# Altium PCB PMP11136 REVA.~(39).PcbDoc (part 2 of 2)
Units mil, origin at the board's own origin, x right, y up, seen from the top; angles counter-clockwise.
Board outline 4320 x 3450 mil, 4 copper layers (Top Layer, Signal Layer 1, Signal Layer 2, Bottom Layer), stack 79.834 mil thick; 234 components, 94 nets, 538 pads, 108 vias.
Unrouted connection lines stored in the file: 420.

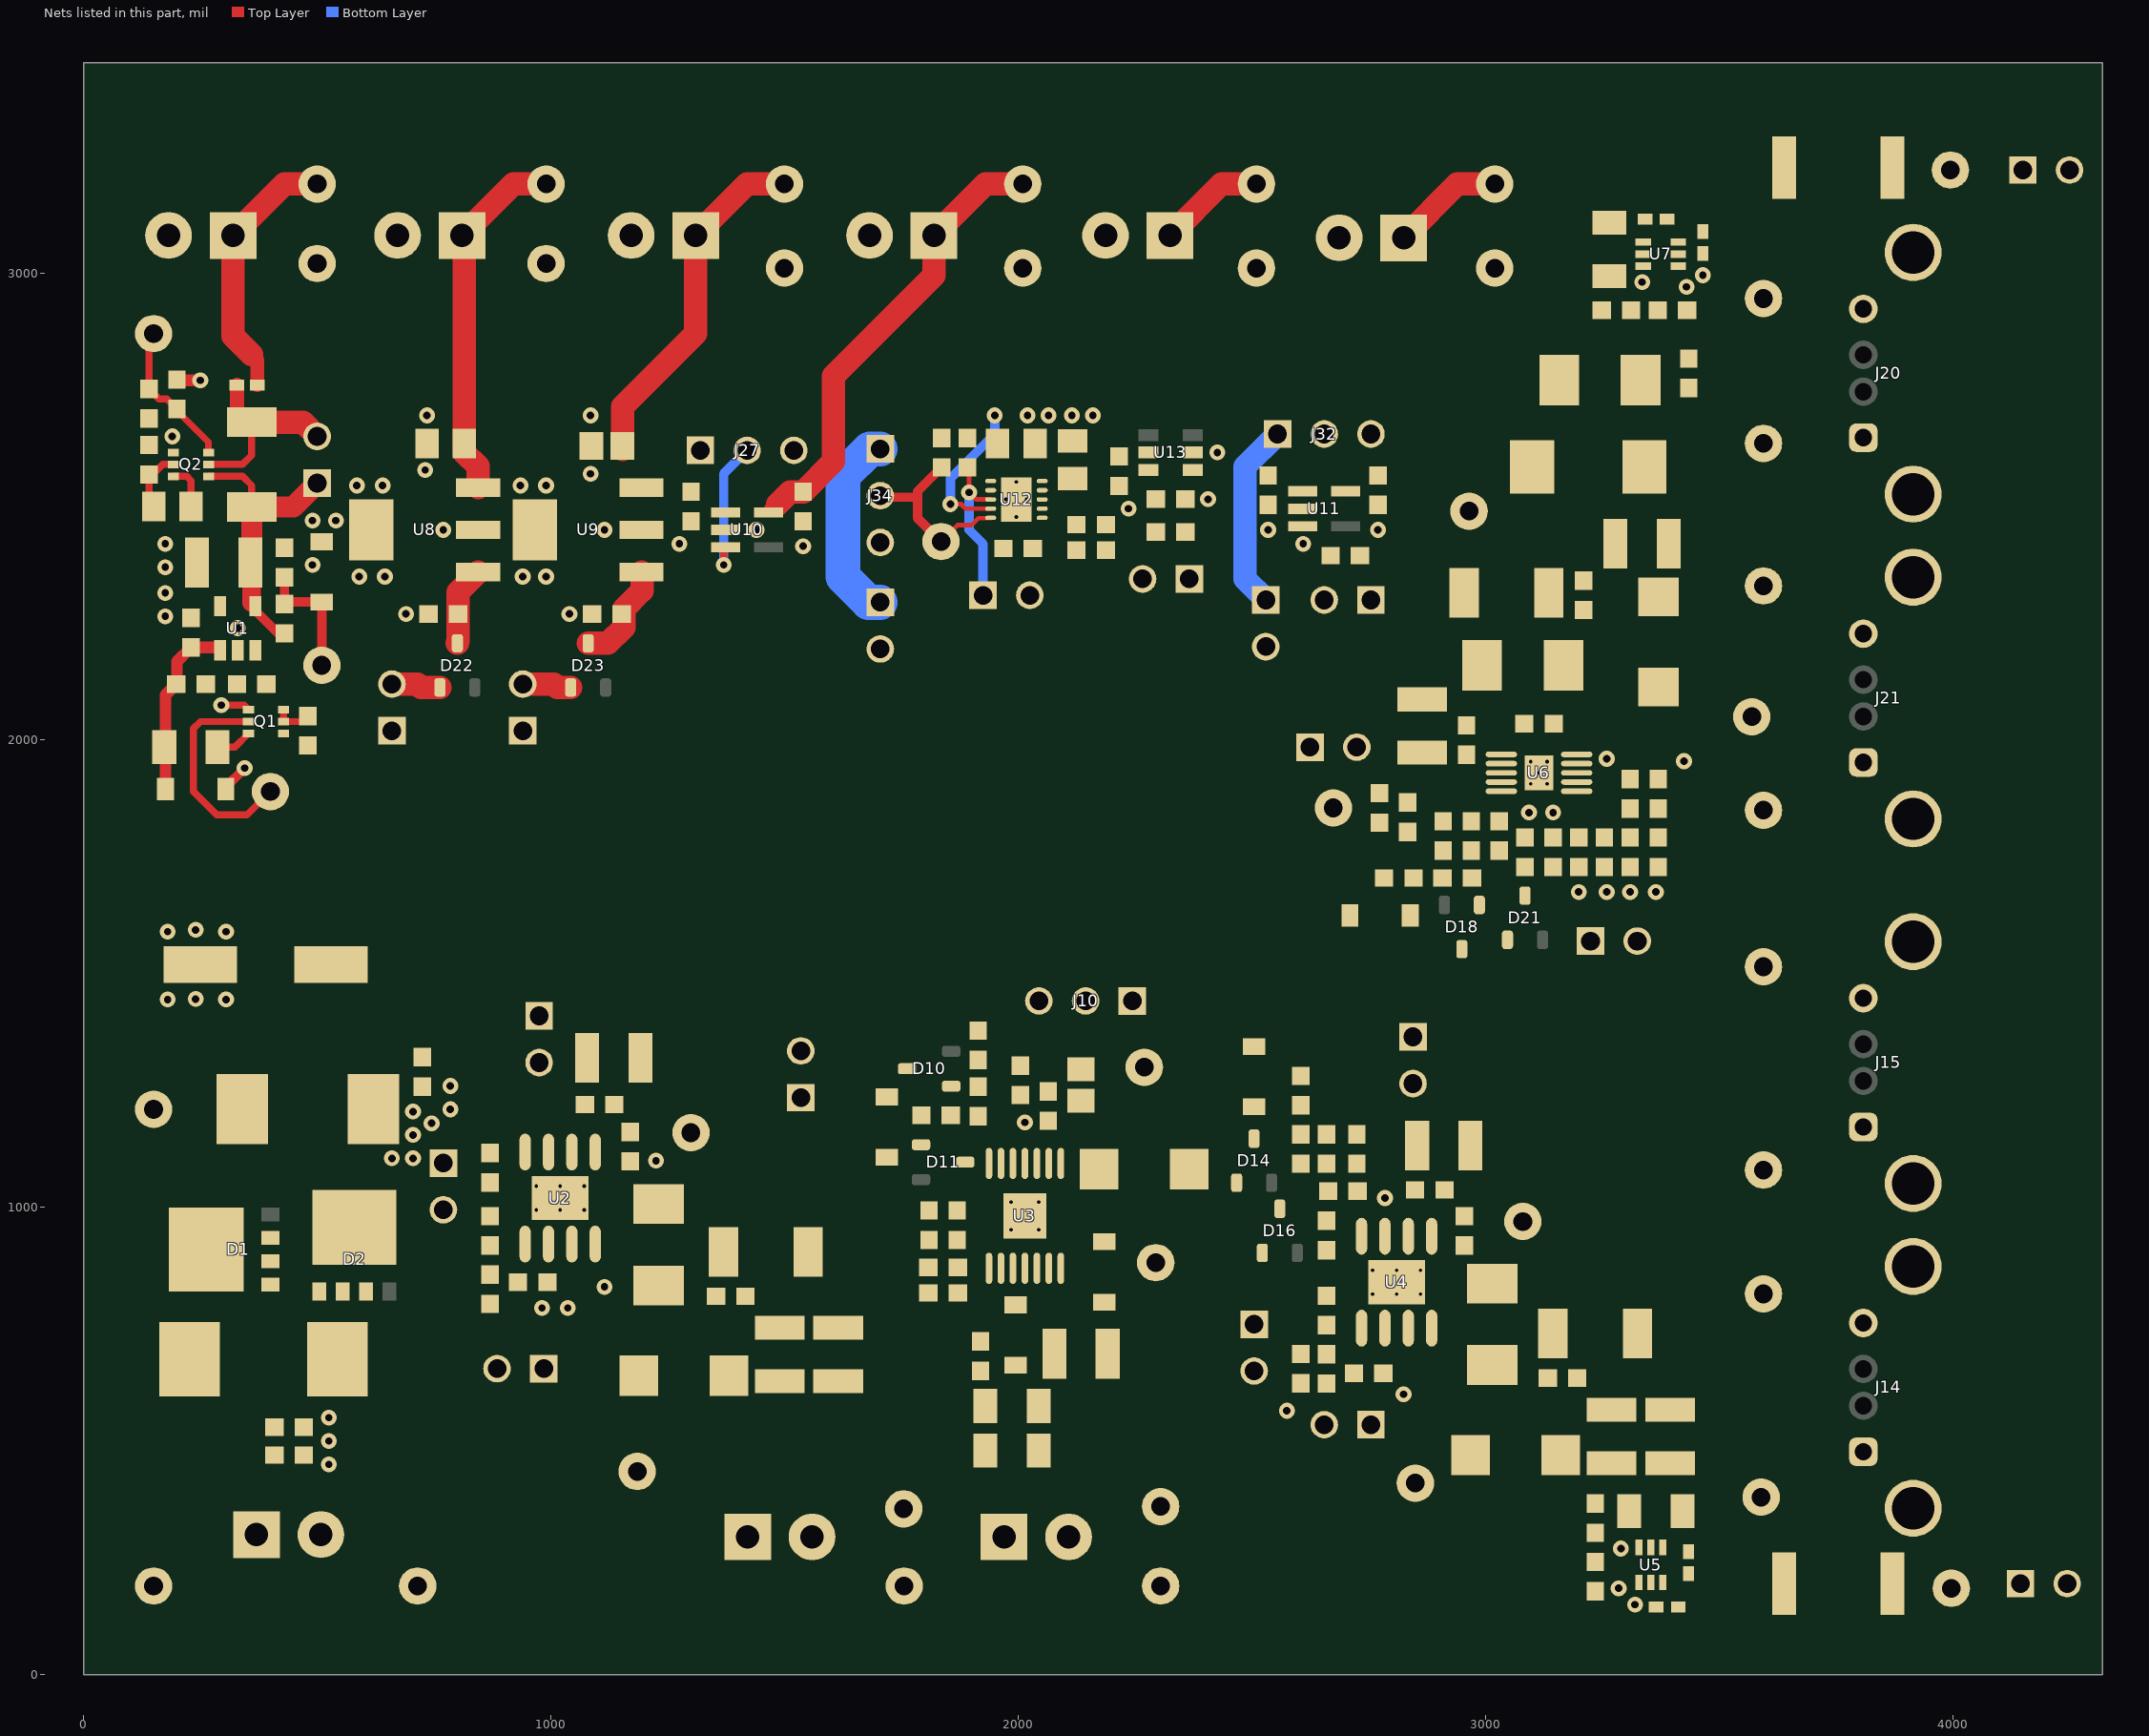
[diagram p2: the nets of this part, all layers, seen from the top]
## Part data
C1 C59: "CAP, CERM, 1000 pF, 100 V, +/- 5%, C0G/NP0, 0603"
C2: "CAP, CERM, 0.01 µF, 100 V, +/- 10%, X7R, 0603"
C3: "CAP, CERM, 0.22 µF, 50 V, +/- 10%, X7R, 0603"
C4: "CAP, AL, 100 µF, 50 V, +/- 20%, 0.34 ohm, SMD"
C5 C9 C22 C32: library part C3225X7R1E106M, "CAP, CERM, 4.7uF, 50V, +/-20%, X7R, 1210"
C6 C13 C51 C52 C54 C55: library part C1608X7R1C105K, "CAP, CERM, 1uF, 25V, +/-10%, X7R, 0603"
C7 C10 C11 C23 C24 C33 C34 C42 C48 C50 C58: "CAP, CERM, 0.1uF, 50V, +/-10%, X7R, 0603"
C8: "CAP, CERM, 0.01 µF, 50 V, +/- 10%, X7R, 0603"
C12 C49: "CAP, CERM, 10uF, 10V, +/-10%, X7R, 0805"
C14 C16 C29 C44: library part C3225X7R1C226M, "CAP, CERM, 22 µF, 16 V, +/- 20%, X7R, 1210"
C15 C20 C27 C39 C40 C57: library part C1608C0G1H102J, "CAP, CERM, open, 0603"
C17 C30: library part C3225X7R1C226M, "CAP, open, 1210"
C18: "CAP, CERM, 0.047 µF, 50 V, +/- 10%, X7R, 0603"
C19 C31 C35: "CAP, CERM, 150 pF, 50 V, +/- 5%, C0G/NP0, 0603"
C21: "CAP, CERM, 6800 pF, 25 V, +/- 5%, C0G/NP0, 0603"
C25 C28 C36 C45: "CAP, CERM, 0.1uF, 50V, +/-10%, X7R, 0402"
C26 C41 C46: "CAP, CERM, 10 pF, 50 V, +/- 5%, C0G/NP0, 0603"
C37: "CAP, CERM, 0.022 µF, 50 V, +/- 10%, X7R, 0603"
C38: "CAP, CERM, 1500 pF, 50 V, +/- 5%, C0G/NP0, 0603"
C43: library part 10TPB220M, "CAP, open, 7343-40 SMD"
C47 C53 C56: "CAP, CERM, 10 µF, 10 V, +/- 10%, X7R, 0805"
D1 D2: "Diode, Schottky, 45 V, 10 A, 6.15x1.00x5.15mm"
D3: library part 1.5SMC6.8A, "Diode, TVS, Uni, 33 V, 1500 W, SMC"
D4: library part 1PS79SB70,115, "Diode, Schottky, 30 V, 0.2 A, SOD-523"
D5: "Diode, Zener, 3.3 V, 500 mW, SOD-123"
D6: "Diode, Zener, 18 V, 500 mW, SOD-123"
D7: library part B130LAW-7-F, "Diode, Schottky, 30V, 1.5A, SOD-123"
D8: "Diode, Zener, 12 V, 500 mW, SOD-123"
D9 D13: library part MBRS260T3G, "Diode, Schottky, 60V, 3A, SMB"
D10 D11 D14 D16 D18 D21 D22 D23: "Diode, Ultrafast, 75V, 0.3A, SOT-23"
D12 D15 D20: "Diode, Zener, 2.4V, 500 mW, SOD-123"
D17 D19: "Diode, Schottky, 60V, 2A, SMB"
J1 J3 J7 J9 J23 J24 J26 J31 J33: "Terminal Block, 6A, 3.5mm Pitch, 2-Pos, TH"
J2 J4 J5 J6 J8 J11 J12 J13 J16 J17 J18 J19 J22 J25 J28 J29 J30 J35 J36: "Header, 100mil, 2x1, Tin, TH"
J10 J27 J32 J34: "Header, 100mil, 3x1, Tin, TH"
J14 J15 J20 J21: "Connector, Receptacle, USB Standard, R/A, Top Mount TH"
L1: "Ferrite Bead, 115 ohm @ 100MHz, 10A, SMD, 2-Leads, Body 8.74x4.65mm"
L2 L4: "Inductor, Wirewound, Ferrite, 2.2 µH, 4.1 A, 0.015 ohm, SMD"
L3 L5: "Inductor, Wirewound, Ferrite, 4.7 µH, 3.1 A, 0.023 ohm, SMD"
Q1: library part "BCR 48PN E6327, Infineon Technologies", "Transistor, NPN/PNP Pair, 50 V, 0.1 A, SOT-363"
Q2: library part "BC 846PN H6327, Infineon Technologies", "Transistor, NPN/PNP Pair, 45 V, 0.1 A, SOT-363"
R1: "RES, 7.5, 5%, 0.75 W, 2010"
R2: "RES, 20.0 k, 1%, 0.1 W, 0603"
R3 R4 R13 R14 R19 R31 R34 R36 R44 R49 R50 R53: "RES, 10.0 k, 1%, 0.1 W, 0603"
R5: "RES, 10.0 k, 1%, 0.125 W, 0805"
R6: "RES, 2.00 k, 1%, 0.25 W, 1206"
R7: "RES, 2.87 k, 1%, 0.1 W, 0603"
R8: "RES, 3.01 k, 1%, 0.1 W, 0603"
R9 R43: "RES, 100 k, 1%, 0.1 W, 0603"
R10: "RES, 34.0 k, 1%, 0.1 W, 0603"
R11: "RES, 110, 1%, 0.1 W, 0603"
R12 R29 R45: library part CRCW20102R70JNEF, "RES, open, 2010"
R15 R26: library part CRCW060312K1FKEA, "RES, 12.1 k, 0.1%, 0.1 W, 0603"
R16: "RES, 53.6 k, 1%, 0.1 W, 0603"
R17 R18: "RES, 15.0, 1%, 0.25 W, 1206"
R20 R28 R38: "RES, 0, 5%, 0.1 W, 0603"
R21 R30 R47: "RES, 200, 1%, 0.1 W, 0603"
R22 R35: "RES, 0.2, 1%, 2 W, 2512"
R23 R37: "RES, 0.01, 1%, 0.5 W, 1206"
R24 R39: "RES, 4.02 k, 1%, 0.1 W, 0603"
R25 R32 R41 R46 R52: "RES, 4.99 k, 1%, 0.1 W, 0603"
R27 R40: "RES, 63.4 k, 1%, 0.1 W, 0603"
R33 R48: "RES, 124 k, 1%, 0.1 W, 0603"
R42: "RES, 54.9 k, 1%, 0.1 W, 0603"
R51: "RES, 2.49 k, 1%, 0.1 W, 0603"
R54: "RES, 49.9 k, 1%, 0.1 W, 0603"
TP1 TP2 TP4 TP6 TP7 TP8 TP9 TP10 TP11 TP12 TP13 TP17 TP19 TP20 TP23 TP25 TP26 TP27 TP30 TP32 TP34 TP36 TP37 TP40 TP41 TP42: "Test Point, Miniature, Red, TH"
TP3 TP5 TP14 TP15 TP16 TP18 TP21 TP22 TP24 TP28 TP29 TP31 TP33 TP35 TP38 TP39: "Test Point, Miniature, Black, TH"
U1: "Low Dropout Voltage Tracking LDO, DBV0005A"
U2 U4: library part LMR14030PDDAR, "LMR14030PQDDAQ1, DDA0008E"
U3: "3-A High Voltage Boost Converter with Soft-start and Programmable Switching Frequency, PWP0014E"
U5 U7: library part INA213AIDCK, "Voltage Output, High or Low Side Measurement, Bi-Directional Zero-Drift Series Current-Shunt Monitor, DCK0006A"
U6: "1.5-A 42-V STEP-DOWN SWIFT DC-DC CONVERTER WITH Eco-mode CONTROL, DGQ0010D"
U8 U9: "High Voltage Ultra Low Iq - Low Drop Out Regulator, DCY0004A"
U10: "Single Output Automotive LDO, 200 mA, Fixed 3.3 V Output, 2 to 5.5 V Input, with Low IQ, 5-pin SOT (DDC), -40 to 125 degC, Green (RoHS & no Sb/Br)"
U11: "Single Output Automotive LDO, 300 mA, Fixed 1.8 V Output, 2 to 5.5 V Input, with Low IQ, 5-pin SOT (DDC), -40 to 125 degC, Green (RoHS & no Sb/Br)"
U12: "Single Output Automotive LDO, 500 mA, Adjustable 0.8 to 3.6 V Output, 0.8 to 5.5 V Input, with Programmable Soft Start, 10-pin SON (DRC), -40 to 125 degC, Green (RoHS & no Sb/Br)"
U13: library part TPS3808G18QDBVRQ1, "LOW-QUIESCENT-CURRENT PROGRAMMABLE-DELAY SUPERVISORY CIRCUIT, DBV0006A"

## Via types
v1: diameter 34, hole 16, Top Layer to Bottom Layer, 83 vias
v2: diameter 19.68, hole 7.87, Top Layer to Bottom Layer, tented top, 12 vias
v3: diameter 19.68, hole 7.87, Top Layer to Bottom Layer, 9 vias
v4: diameter 15.75, hole 7.87, Top Layer to Bottom Layer, 4 vias

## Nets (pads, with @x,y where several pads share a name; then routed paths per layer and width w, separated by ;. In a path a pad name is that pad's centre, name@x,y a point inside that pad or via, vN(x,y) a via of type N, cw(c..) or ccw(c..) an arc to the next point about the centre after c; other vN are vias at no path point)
"3.3V PG": J8.1 J35.2 R13.2 U2.6
  other v1: 981.3,785
3.3V_SW: C16.1 C17.1 C58.1 J6.1 J9.1 J28.2 J29.2 L2.2 R4.2 R10.2 R13.1 R34.1 R36.1 R54.2 TP13.1 U13.6 | length 50.6
  Top Layer w25: R4.2@200,2771.5 201.5,2770 v1(250,2770)
5V#1PG: J16.1 R34.2 U4.6
GND: C1.2 C2.2 C3.2 C4.2 C5.1 C6.2 C7.2 C8.2 C9.1 C10.2 C12.2 C13.2 C14.2 C16.2 C17.2 C18.2 C20.2 C21.2 C22.1 C23.2 C25.2 C28.2 C29.2 C30.2 C32.1 C33.2 C36.2 C37.2 C40.2 C42.2 C43.2 C44.2 C45.2 C46.2 C47.2 C48.2 C49.2 C50.2 C51.2 C52.2 C53.2 C54.2 C55.2 C56.2 C57.2 C58.2 C59.2 D3.2 D5.2 D6.2 D9.2 D11.1 D12.2 D13.2 D15.2 D16.1 D19.2 D20.2 D21.1 J1.2 J3.2 J5.2 J8.2 J9.2 J10.3 J12.2 J13.2 J14.4 J14.5 J14.6 J15.4 J15.5 J15.6 J16.2 J18.2 J19.2 J20.4 J20.5 J20.6 J21.4 J21.5 J21.6 J23.2 J24.2 J26.2 J27.3 J30.2 J31.2 J32.3 J33.2 J34.3 J36.2 Q1.1 Q2.1 R7.2 R8.1 R9.2 R12.1 R14.1 R15.1 R16.1 R17.1 R18.1 R21.1 R29.1 R30.1 R31.1 R32.2 R43.1 R44.1 R45.1 R46.2 R47.1 R52.1 TP3.1 TP5.1 TP15.1 TP16.1 TP18.1 TP21.1 TP22.1 TP24.1 TP28.1 TP29.1 TP31.1 TP33.1 TP35.1 TP38.1 TP39.1 U1.2 U1.5 U2.7 U2.9 U3.7 U3.11 U3.12 U3.13 U3.14 U3.15 U4.7 U4.9 U5.2 U6.9 U6.11 U7.2 U8.2 U8.4 U9.2 U9.4 U10.2 U11.2 U12.6 U12.11 U13.2 | length 123.7
  Top Layer w15: v1(295,2075) 343.31,2075 Q1.1@352.95,2065.36
  Top Layer w20: D6.2@304.47,1895 304.47,1899.47 v1(345,1940)
  other v1: 3320,150 3285,185 525,450 525,500 525,550 2825,600 1036.3,785 660,1105 705,1105 705,1155 745,1180 705,1205 785,1210 785,1260 180,1445 305,1445 239.95,1446 180,1590 305,1590 239.95,1594 3199.68,1675 3364.68,1675 3093.23,1845 3425,1955 3259.68,1960 330,2239.68 175,2265 690,2270 1040,2270 175,2315 590,2350 645,2350 940,2350 990,2350 175,2370 490,2375 1540,2415 175,2420 1275,2420 770,2450 1115,2450 1440,2450 2535,2450 2770,2450 490,2470 540,2470 2236.3,2495.47 2406.3,2515.47 585,2545 640,2545 935,2545 990,2545 1085,2570 730.98,2577.95 2426.3,2615.47 190,2650 735,2695 1085,2695 2020,2695 2065,2695 2115,2695 2160,2695 3430.31,2970 3465.31,2995
  other v2: 2758.82,814.41 2810,814.41 2861.18,814.41 2758.82,865.59 2810,865.59 2861.18,865.59 968.82,994.41 1020,994.41 1071.18,994.41 968.82,1045.59 1020,1045.59 1071.18,1045.59
  other v3: 1996.3,2477.6 1973.66,2515 2018.94,2515 1996.3,2552.4
  other v4: 1984.96,952.38 2044.02,952.38 1984.96,1011.44 2044.02,1011.44
NetC1_1: C1.1 C2.1 J1.1 L1.1 TP1.1
NetC5_2: C5.2 J2.1 Q2.4 R1.1 R3.2 U1.4 | length 615.1
  Top Layer w15: Q2.4@267.4,2564.41 340.59,2564.41 360,2545 R1.1@360,2499.13
  Top Layer w20: U1.4@367.4,2286.93 367.4,2277.6 416.5,2228.5 R3.2@430,2228.5
  Top Layer w25: U1.4@360,2294.33 U1.4@367.4,2286.93
  Top Layer w40: U1.4@360,2294.33 C5.2@360,2377.09
  Top Layer w45: C5.2@360,2377.09 R1.1@360,2499.13 449.13,2499.13 J2.1@500,2550
NetC7_1: C7.1 Q2.6 R4.1 TP6.1 | length 321.3
  Top Layer w15: TP6.1@150,2870 140,2860 C7.1@140,2751.5 161.5,2730 178.5,2730 R4.1@200,2708.5 200,2705 267.4,2637.6 Q2.6@267.4,2615.59
NetC8_1: C8.1 D6.1 R6.2 R9.1 U1.1 | length 391.2
  Top Layer w25: D6.1@175.53,1895 175.53,2097.03 R9.1@198.5,2120 200,2121.5 200,2168.5 C8.1@230,2198.5 286.54,2198.5 U1.1@292.6,2192.44
NetC9_2: C9.2 C10.1 J4.2 U2.2
NetC11_1: C11.1 U2.1
NetC12_1: C12.1 C13.1 J6.2 J10.1 L3.1 TP10.1 U3.3
NetC14_1: C14.1 D7.1 D8.1 J7.2 TP12.1
NetC15_2: C15.2 R12.2
NetC18_1: C18.1 U3.5
NetC19_1: C19.1 D10.1 D11.3 R21.2 U3.6
NetC19_2: C19.2 R20.2
NetC20_1: C20.1 R19.2 U3.8
NetC21_1: C21.1 R19.1
NetC22_2: C22.2 C23.1 J11.2 U4.2
NetC24_1: C24.1 U4.1
NetC24_2: C24.2 C27.1 D13.1 L4.1 TP19.1 U4.8
NetC25_1: C25.1 C29.1 C30.1 J15.1 L4.2 R23.1 R25.1 R27.2 TP20.1 U5.3 U5.5
NetC26_1: C26.1 R24.2
NetC26_2: C26.2 C31.1 D14.1 D16.3 R26.1 R30.2
NetC27_2: C27.2 R29.2
NetC28_1: C28.1 J14.1 R22.1 R23.2 TP41.1 U5.4
NetC31_2: C31.2 R28.2
NetC32_2: C32.2 C33.1 J17.2 U6.2
NetC34_1: C34.1 U6.1
NetC34_2: C34.2 C39.1 D19.1 L5.1 TP26.1 U6.10
NetC35_1: C35.1 C41.2 D18.1 D21.3 R42.1 R47.2
NetC35_2: C35.2 R38.2
NetC36_1: C36.1 C42.1 D17.1 J21.1 R37.1 R40.2 R41.1 TP27.1 U7.3 U7.5
  other v1: 3259.68,1675
NetC37_1: C37.1 U6.4
NetC38_1: C38.1 C46.1 U6.8
NetC38_2: C38.2 R43.2
NetC39_2: C39.2 R45.2
NetC40_1: C40.1 TP25.1 U6.3
NetC41_1: C41.1 R39.2
NetC43_1: C43.1 C44.1 D17.2 L5.2
NetC45_1: C45.1 J20.1 R35.1 R37.2 TP42.1 U7.4
NetC47_1: C47.1 J23.1 TP30.1 U8.3 | length 779.2
  Top Layer w50: U8.3@844.17,2540.55 844.17,2585.83 815,2615 C47.1@815,2635 815,3075 J23.1@810,3080 920,3190 TP30.1@990,3190
NetC48_1: C48.1 D22.3 U8.1 | length 170.5
  Top Layer w50: D22.3@800,2207.24 800.39,2207.64 800.39,2210.39 801.5,2211.5 C48.1@801.5,2270 801.5,2316.77 U8.1@844.17,2359.45
NetC49_1: C49.1 C51.1 J24.1 J27.1 TP32.1 U9.3 U10.1 | length 758.2
  Top Layer w50: C49.1@1153.46,2622.17 C49.1@1153.46,2630 1153.46,2713.46 1310,2870 J24.1@1310,3080 1420,3190 TP32.1@1500,3190
NetC50_1: C50.1 D23.3 U9.1 | length 224.9
  Top Layer w50: D23.3@1080,2207.24 1122.24,2207.24 1156.46,2241.46 1156.46,2281.46 1195,2320 1195,2358.62 U9.1@1194.17,2359.45
NetC52_1: C52.1 J26.1 TP34.1 U10.5 | length 997.3
  Top Layer w20: U10.5@1466,2487.4 1466,2496 1475,2505
  Top Layer w30: 1475,2505 1485,2505
  Top Layer w50: 1485,2505 1511.5,2531.5 C52.1@1540,2531.5 1605,2596.5 1605,2779 1820,2994 J26.1@1820,3080 1930,3190 TP34.1@2010,3190
NetC53_1: C53.1 J28.1 J34.1 R49.2 R50.2 U12.1 U12.2 U12.4 | length 741.4
  Top Layer w10: v1(1855,2505) 1877.75,2505 1887.44,2495.32 U12.4@1941.18,2495.32
  Bottom Layer w20: v1(1855,2505) 1855,2560 1950,2655 v1(1950,2695)
  Bottom Layer w75: J28.1@1705,2295 1680,2295 1625,2350 1625,2565 1683.02,2623.02 J34.1@1705,2623.02
NetC54_1: C54.1 J31.1 TP37.1 U11.5 | length 242.6
  Top Layer w50: J31.1@2825,3075 2940,3190 TP37.1@3020,3190
NetC55_1: C55.1 J29.1 J32.1 U11.1 | length 402.6
  Bottom Layer w50: J29.1@2530,2300 2485,2345 2485,2585 J32.1@2555,2655
NetC56_1: C56.1 C59.1 J33.1 R51.2 TP36.1 U12.9 U12.10 U13.5 | length 230.6
  Top Layer w50: J33.1@2325,3080 2435,3190 TP36.1@2510,3190
NetC57_1: C57.1 U12.7
NetD1_1: D1.1 D1.2 D1.3 D2.1 D2.2 D2.3 L1.2
NetD4_1: D4.1 J3.1 TP4.1 | length 567
  Top Layer w30: 360,2825 371.65,2813.35 D4.1@371.65,2760
  Top Layer w50: 360,2825 320,2865 J3.1@320,3080 430,3190 TP4.1@500,3190
NetD4_2: D4.2 J2.2 Q2.5 R1.2 | length 416.5
  Top Layer w15: Q2.5@267.4,2590 340,2590 360,2610 R1.2@360,2680.24
  Top Layer w20: 328.35,2711.89 R1.2@360,2680.24
  Top Layer w30: 328.35,2711.89 D4.2@328.35,2760
  Top Layer w50: R1.2@360,2680.24 360.24,2680 470,2680 J2.2@500,2650
NetD5_1: D5.1 R3.1 R7.1 TP7.1 | length 274.2
  Top Layer w20: R7.1@430,2348.5 R3.1@430,2291.5 434.04,2295.53 D5.1@510,2295.53 TP7.1@510,2160
NetD7_2: D7.2 L3.2 TP11.1 U3.1 U3.2
NetD8_2: D8.2 R11.2 U3.9
NetD10_3: D10.3 D12.1
NetD14_3: D14.3 D15.1
NetD18_3: D18.3 D20.1
NetD22_1: D22.1 J22.2 | length 105.6
  Top Layer w50: J22.2@660,2120 715,2120 722.24,2112.76 D22.1@762.6,2112.76
NetD23_1: D23.1 J25.2 | length 105.6
  Top Layer w50: J25.2@940,2120 1006.61,2120 1013.86,2112.76 D23.1@1042.6,2112.76
NetJ5_1: J5.1 U2.3
NetJ7_1: J7.1 R11.1 R17.2 R18.2 TP14.1
NetJ10_2: J10.2 U3.4
  other v1: 2014.49,1181.91
NetJ12_1: J12.1 R22.2 TP17.1
NetJ13_1: J13.1 U4.3
  other v1: 2785,1020
NetJ18_1: J18.1 R36.2 U6.6
  other v1: 3144.68,1845
NetJ19_1: J19.1 R35.2 TP23.1
NetJ27_2: J27.2 U10.3 | length 305
  Top Layer w15: v1(1370,2375) 1370,2408.6 U10.3@1374,2412.6
  Bottom Layer w20: v1(1370,2375) 1370,2570 J27.2@1420,2620
NetJ30_1: J30.1 R49.1 U12.3 | length 339.9
  Top Layer w10: R49.1@1891.3,2583.5 1891.3,2568.7 1895,2565 v1(1895,2530) 1910,2515 U12.3@1941.18,2515
  Bottom Layer w20: v1(1895,2530) 1895,2450 1925,2420 J30.1@1925,2310
NetJ32_2: J32.2 R53.2 U11.3
  other v1: 2610,2420
NetJ34_2: J34.2 R50.1 TP40.1 U12.5 | length 408.9
  Top Layer w10: TP40.1@1835,2425 1870,2460 1900,2460 1915,2475 1940.55,2475 U12.5@1941.18,2475.63
  Top Layer w20: J34.2@1705,2523.02 1708.02,2520 1785,2520 ; TP40.1@1835,2425 1785,2475 1785,2520 ; R50.1@1836.3,2583.5 1785,2532.2 1785,2520
NetJ35_1: J35.1 R53.1
NetJ36_1: J36.1 R54.1 U13.1
NetQ1_2: Q1.2 TP8.1 | length 465.2
  Top Layer w15: Q1.2@352.95,2039.77 250.23,2039.77 235,2024.54 235,1890 285,1840 350,1840 TP8.1@400,1890
NetQ1_3: Q1.3 R6.1 | length 77.9
  Top Layer w15: R6.1@287.09,1985 323.77,1985 Q1.3@352.95,2014.18
NetQ1_5: Q1.5 Q1.6 R2.1 | length 82.7
  Top Layer w15: Q1.6@427.75,2065.36 Q1.5@427.75,2039.77 468.27,2039.77 R2.1@480,2051.5
NetQ2_2: Q2.2 R5.1 R8.2 | length 134.1
  Top Layer w15: R5.1@150,2500 140,2510 R8.2@140,2568.5 148.5,2568.5 170,2590 Q2.2@192.6,2590
NetQ2_3: Q2.3 R5.2 | length 96.3
  Top Layer w15: Q2.3@192.6,2564.41 220.59,2564.41 230,2555 R5.2@230,2500
NetR10_1: R10.1 R14.2 U2.5
NetR15_2: R15.2 U2.4
NetR16_2: R16.2 U3.10
NetR24_1: R24.1 R26.2 U4.4
NetR25_2: R25.2 R32.1 U5.1
NetR27_1: R27.1 R31.2 R33.2 U4.5
NetR33_1: R33.1 U5.6
  other v1: 3290,270 2575,565
NetR39_1: R39.1 R42.2 U6.5
NetR40_1: R40.1 R44.2 R48.2 U6.7
  other v3: 3096.97,1906.38 3132.4,1906.38 3114.68,1930 3096.97,1953.62 3132.4,1953.62
NetR41_2: R41.2 R46.1 U7.1
NetR48_1: R48.1 U7.6
  other v1: 3309.68,1675 3335.31,2980
NetR51_1: R51.1 R52.2 U12.8
SYNC: C11.2 C15.1 D9.1 L2.1 R20.1 R28.1 R38.1 TP9.1 U2.8
  other v1: 1115,830 1225,1100
VIN_FLTR: C3.1 C4.1 C6.1 D1.5 D2.5 D3.1 J4.1 J11.1 J17.1 J22.1 J25.1 Q1.4 R2.2 TP2.1 U1.3
pads on no net: D1.4 D2.4 D10.2 D11.2 D14.2 D16.2 D18.2 D21.2 D22.2 D23.2 J14.2 J14.3 J15.2 J15.3 J20.2 J20.3 J21.2 J21.3 U10.4 U11.4 U13.3 U13.4

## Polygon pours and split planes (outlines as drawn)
NetC53_1 on Top Layer "Top Layer-No Net 6" (solid, remove dead copper, pour order 27): 1675,2590 1755,2590 1790,2625 1895,2625 1909.84,2625 1919.84,2615 1922.3,2612.54 1922.3,2605 1922.3,2532.7 1925,2530 1945,2530 1950,2530 1950,2531.09 1957.25,2538.34 1960,2541.09 1960,2575 1980,2595 1980,2606.46 1980,2750 1965,2765 1805,2765 1690,2765 1675,2750
NetC49_1 on Top Layer "Top Layer-No Net 5" (solid, remove dead copper, pour order 25): 1318.7,2515 1155,2515 1130,2540 1130,2650 1345,2650 1350,2645 1350,2620 1350,2590 1375,2565 1385.48,2554.52 1385.48,2477.42 1342.58,2477.42 1305,2515
VIN_FLTR on Top Layer "Top Layer-No Net 4" (solid, remove dead copper, pour order 23): 498.7,2010 431.93,2010 427.75,2014.18 426.93,2015 405,2015 400,2020 400,2110 400,2182.76 375.95,2206.82 355,2185.87 355,2160.94 355,2153.39 370,2138.39 375,2133.39 375,1990 375,1985 390,1970 495,1970
VIN_FLTR on Top Layer "Top Layer-No Net 3" (solid, remove dead copper, pour order 21): 1005,1675 1005,2035 990,2050 620,2050 560,2050 515,2005 461.3,2005 461.3,1861.3 430,1830 350,1750 350,1675
VIN_FLTR on Top Layer "Top Layer-No Net 2" (solid, remove dead copper, pour order 19): 690,875 490,875 490,875.12 470.75,894.37 470,895.12 470,960 470,985 455,1000 355,1000 330,975 330,860 330,855 340,845 340,795 340,785 330,775 130,775 0,775 0,1420 325,1420 345,1440 350,1445 350,1580 350,1595 350,1700 990,1700 1000,1690 1005,1685 1005,1600 1005,1380 845,1380 823.7,1380 743.7,1300 738.7,1305 630,1305 555,1305 545,1295 545,1225 545,1130 560,1115 625,1115 625,1100 650,1075 670,1075 680,1075 690,1065 690,900
NetD1_1 on Top Layer "Top Layer-No Net 1" (solid, remove dead copper, pour order 17): 360,950 360,785 360,775 340,755 330,745 330,740 330,610 340,600 345,595 620,595 620,855 495,855 470,855 450,875 450,930 450,950
NetC1_1 on Top Layer "Top Layer-No Net" (solid, remove dead copper, pour order 15): 0,0 430,0 430,565 415,580 350,580 340,580 315,605 315,755 0,755

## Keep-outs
Keep-Out Layer:
  the board outline again, w7
  text ".Layer_Name" at 577,-858.49 h60

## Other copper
Top Layer:
  text ".Layer_Name" at 577,-858.49 h60
Bottom Layer:
  text ".Layer_Name" at 577,-858.49 h60

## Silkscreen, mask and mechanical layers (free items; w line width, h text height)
Top Overlay:
  text ".PRJ_Number" at 1375,1745 h60
  text ".PCB_Rev" at 1975,1745 h60
  text ".Layer_Name" at 577,-858.49 h60
Bottom Overlay:
  text ".Layer_Name" at 577,-858.49 h60
Top Paste:
  text ".Layer_Name" at 577,-858.49 h60
Bottom Paste:
  text ".Layer_Name" at 577,-858.49 h60
Top Solder:
  text ".Layer_Name" at 577,-858.49 h60
  text ".Layer_Name" at 577,-858.49 h60
Bottom Solder:
  text ".Layer_Name" at 577,-858.49 h60
Drill Guide:
  text ".Layer_Name" at 577,-858.49 h60
M1 Board Outline:
  lines w7: 0,0 4320,0 4320,3450 0,3450 0,0
  lines w10: 0,0 4320,0 4320,3450 0,3450 0,0
  text ".Layer_Name" at 577,-858.49 h60
M2 Board Dimensions:
  rectangle: 125,-400 500,-275
  rectangle: 0,-275 125,-150
  lines w7: 0,-275 1000,-275 ; 125,-400 125,-150 ; 250,-400 250,-150 ; 500,-400 500,-150 ; 750,-400 750,-150 ; 0,-400 0,-150 1000,-150 1000,-400 0,-400
  text ".Layer_Name" at 577,-858.49 h60
M3 3D STEP Top:
  text ".Layer_Name" at 577,-858.49 h60
M4 3D STEP Bottom:
  text ".Layer_Name" at 577,-858.49 h60
M5 Assembly Top:
  lines w10: -292,-930.17 6308,-930.17 ; -292,-726.83 6310,-726.83 ; -292,-523.5 -292,-1133.5 3713,-1133.5 6310,-1133.5 6310,-523.5 -291.5,-523.5 -291.5,-1133.5 1284,-1133.5 ; 2173,-1133.5 2173,-523.5 ; 3440,-726.83 3440,-523.5 ; 4280,-726.83 4280,-523.5 ; 4902,-1140 4902,-937.17
  text "COMPONENTS MARKED 'DNP' SHOULD NOT BE POPULATED." at 1153.5,-318.5 h60
  text "ASSEMBLY VARIANT:" at 1153,-434 h60
  text ".VariantName" at 2189,-434 h60
  text "PCB VIEWED FROM TOP SIDE" at -228.5,-655.67 h60
  text "BOARD #:" at 2248,-655.67 h60
  text ".PRJ_Number" at 2793.5,-655.67 h60
  text "REV:" at 3638,-655.67 h60
  text ".PCB_Rev" at 3929.5,-655.67 h60
  text "SVN REV:" at 4476,-655.67 h60
  text ".VersionControl_RevNumber" at 4982,-655.67 h60
  text "PLOT NAME =" at -228.5,-1064.34 h60
  text ".plot_File_Name" at 577,-1064.34 h60
  text "GENERATED    :" at 2250,-1064.34 h60
  text ".Print_Date" at 3119.5,-1064.34 h60
  text ".Print_Time" at 3848.5,-1064.34 h60
  text "TEXAS INSTRUMENTS" at 5113,-1064.34 h60
M6 Assembly Bottom:
  lines w10: -292.5,-727.33 6309.5,-727.33 ; -290.5,-930.67 6309.5,-930.67 ; 1115.5,-1140.5 1115.5,-937.67 ; 1737.5,-727.33 1737.5,-524 ; 2577.5,-727.33 2577.5,-524 ; 3844.5,-1134 3844.5,-524 ; 4733.5,-1134 6309,-1134 6309,-524 -292.5,-524 -292.5,-1134 2304.5,-1134 6309.5,-1134 6309.5,-524
  text "COMPONENTS MARKED 'DNP' SHOULD NOT BE POPULATED." at 6102,-318 h60
  text ".VariantName" at 5058,-434 h60
  text "ASSEMBLY VARIANT:" at 6097,-434 h60
  text ".VersionControl_RevNumber" at 1035.5,-656.17 h60
  text "SVN REV:" at 1541.5,-656.17 h60
  text ".PCB_Rev" at 2088,-656.17 h60
  text "REV:" at 2379.5,-656.17 h60
  text ".PRJ_Number" at 3224,-656.17 h60
  text "BOARD #:" at 3769.5,-656.17 h60
  text "PCB VIEWED FROM BOTTOM SIDE" at 6246,-656.17 h60
  text "TEXAS INSTRUMENTS" at 904.5,-1064.84 h60
  text ".Print_Time" at 2169,-1064.84 h60
  text ".Print_Date" at 2898,-1064.84 h60
  text "GENERATED    :" at 3767.5,-1064.84 h60
  text ".plot_File_Name" at 5440.5,-1064.84 h60
  text "PLOT NAME =" at 6246,-1064.84 h60
M9 Title Sheet:
  drawing of 57 lines, arcs and shapes, not listed
  text "1" at 739.84,8036.5 h70
  text "2" at 3235.5,8036.5 h70
  text "3" at 5724.84,8036.5 h70
  text "4" at 8231.51,8036.5 h70
  text "5" at 10730.5,8036.5 h70
  text "6" at 13235.5,8036.5 h70
  text "A" at -416.5,6893.5 h70
  text "A" at 14383.5,6893.5 h70
  text "B" at -416.5,4513.5 h70
  text "B" at 14383.5,4513.5 h70
  text "C" at -416.5,2138.5 h70
  text "C" at 14383.5,2138.5 h70
  text "PROJECT TITLE:" at 11343.5,277.5 h45
  text ".PRJ_Title" at 11393.5,144.17 h70
  text "DESIGNED FOR:" at 11343.5,-23.5 h45
  text ".PRJ_Customer" at 11393.5,-163.5 h70
  text "D" at -416.5,-231.5 h70
  text "D" at 14383.5,-231.5 h70
  text "FILE NAME:" at 11343.5,-323.5 h45
  text ".PCB_File_Name_No_Path" at 11393.5,-443.5 h70
  text "Texas Instruments (TI) and/or its licensors do not warrant the accuracy or completeness of this specification" at 6374,-605.34 h45
  text "ENGINEER:" at 11343.5,-613.5 h45
  text "LAYOUT BY:" at 12848.5,-613.5 h45
  text "or any information contained therein. TI and/or its licensors do not warrant that this design will meet" at 6329.01,-718 h45
  text ".PRJ_Engineer" at 11393.5,-768.49 h70
  text ".PCB_Layout" at 12899,-768.49 h70
  text "the specifications, will be suitable for your application or fit for any particular purpose, or will operate in" at 6329.01,-830.67 h45
  text ".Layer_Name" at 577,-858.49 h60
  text "ALTIUM DESIGNER VERSION:" at 12848.5,-923.5 h45
  text "an implementation. TI and/or its licensors do not warrant that the design is production worthy. You should" at 6329.01,-943.33 h45
  text "completely validate and test your design implementation to confirm the system functionality for your application." at 6374,-1056 h45
  text ".print_Scale" at 11393.5,-1056.83 h70
  text ".Application_BuildNumber" at 12899,-1056.83 h70
  text "1" at 739.84,-1263.5 h70
  text "2" at 3235.5,-1263.5 h70
  text "3" at 5724.84,-1263.5 h70
  text "4" at 8231.51,-1263.5 h70
  text "5" at 10730.5,-1263.5 h70
  text "6" at 13235.5,-1263.5 h70
M10 Fab Notes:
  drawing of 185 lines, arcs and shapes, not listed
  text "DESIGN INFORMATION" at 12381.02,5910 h60
  text "MIN. TRACK WIDTH:" at 11736.46,5730 h60
  text "8" at 12832.7,5730 h60
  text "MIL" at 12987.46,5730 h60
  text "MIN. CLEARANCE:" at 11736.46,5598 h60
  text "0.2" at 12772.7,5598 h60
  text "mm" at 12987.46,5598 h60
  text "MIN. VIA PAD SIZE:" at 11736.46,5466 h60
  text "24" at 12802.71,5466 h60
  text "MIL" at 12987.46,5466 h60
  text "0.05mm (2MIL)" at 12431.46,5324.29 h60
  text "MINIMUM ANNULAR RING" at 11407.23,5320 h60
  text "EXTERNAL" at 13139.46,5320 h60
  text "PER" at 11607.23,5202 h60
  text "IPC-D-275 CLASS 2 LEVEL C" at 11827.23,5202 h60
  text "MIL, HOLES" at 13315.46,5089.71 h60
  text "+/-" at 12923,5089 h60
  text "+/-" at 13777,5089 h60
  text "REGISTRATION TOLERANCES:" at 11407.23,5084 h60
  text "METAL" at 12607,5084 h60
  text "5" at 13183.2,5084 h60
  text "3" at 14016.2,5084 h60
  text "MIL" at 14132.46,5084 h60
  text "MATERIAL:" at 11332.46,4874.54 h60
  text "FR-4 High Tg" at 12318.9,4734.21 h60
  text "FR-408" at 11753.46,4725.64 h60
  text "X" at 12165.46,4725.64 h60
  text "OTHER" at 13241.46,4725.64 h60
  text "62 MIL (1.6mm) +/-10%" at 12073.56,4562.92 h60
  text "THICKNESS:" at 11407.23,4558.64 h60
  text "X" at 11945.4,4558.64 h60
  text "OTHER" at 13358.46,4558.64 h60
  text "TOLERANCE:" at 11407.23,4400.64 h60
  text "X" at 12246.53,4400.64 h60
  text "ANSI IPC-6012 TYPE 3 CLASS 2" at 12433.48,4400.64 h60
  text "OTHER +/-" at 12433.46,4244.64 h60
  text "BOW & TWIST:" at 11407.23,4087.64 h60
  text "X" at 12246.53,4087.64 h60
  text "ANSI IPC-6012 TYPE 3 CLASS 2" at 12433.48,4087.64 h60
  text "OTHER +/-" at 12433.46,3929.13 h60
  text "DRILLING:" at 11332.46,3790.64 h60
  text "REFERENCE:" at 11407.23,3673.64 h60
  text "X" at 12055.46,3673.64 h60
  text "AS SHOWN" at 12242.46,3673.64 h60
  text "X" at 12956.46,3673.64 h60
  text "NC_DRILL FILES" at 13093.46,3673.64 h60
  text "PTH MIN COPPER THICKNESS:" at 11407.23,3515.64 h60
  text "X" at 12757.46,3515.64 h60
  text "1MIL" at 12894.46,3515.64 h60
  text "OTHER" at 13391.46,3515.64 h60
  text "BOARD FINISH:" at 11332.46,3356.64 h60
  text "SILKSCREEN:" at 11487.68,3238.64 h60
  text "X" at 12436.46,3238.64 h60
  text "TOP" at 12562.46,3238.64 h60
  text "X" at 12946.46,3238.64 h60
  text "BOTTOM" at 13073.46,3238.64 h60
  text "SILKSCREEN COLOR:" at 11487.68,3071.64 h60
  text "X" at 12435.42,3071.64 h60
  text "WHITE" at 12562.46,3071.64 h60
  text "OTHER" at 13073.46,3071.64 h60
  text "SOLDER RESIST COLOR:" at 11487.68,2901.64 h60
  text "GREEN" at 12182.46,2742.44 h60
  text "BLUE" at 12773.46,2742.44 h60
  text "OTHER" at 13311.46,2742.44 h60
  text "X" at 12650,2740 h60
  text "IMMERSION GOLD (ENIG)" at 12393.46,2553.92 h60
  text "ENEPIG" at 13731,2550.64 h60
  text "SURFACE FINISH:" at 11332.46,2549.64 h60
  text "X" at 11520,2395 h60
  text "IMM. TIN/SILVER OR EQUIV" at 11662,2392.64 h60
  text "OTHER" at 13093.46,2392.64 h60
  text "ARRAY/PANEL:" at 11332.46,2213.64 h60
  text "CUT AND TRIM PER MECH LAYER 1" at 12393.46,2209.35 h60
  text "N.C. ROUTE" at 12393.46,2057.64 h60
  text "X" at 13072.46,2057.64 h60
  text "V. SCORE" at 13259.46,2057.64 h60
  text "CERTIFICATION:" at 11332.46,1920.64 h60
  text "MATERIALS AND WORKMANSHIP FOR ALL PCBS" at 12057.46,1920.64 h60
  text "TO MEET OR EXCEED THE REQUIREMENTS OF:" at 12057.46,1822.64 h60
  text "X" at 11683.96,1686.13 h60
  text "ANSI IPC-A-600F CLASS ->" at 11822.96,1686.13 h60
  text "X" at 13462.02,1686.13 h60
  text "2" at 13580.96,1686.14 h60
  text "1" at 13265.96,1684.64 h60
  text "3" at 13934.96,1684.64 h60
  text "X" at 11686.02,1526.64 h60
  text "UL 94V-0" at 11822.96,1526.64 h60
  text "X" at 12498.02,1526.64 h60
  text "RoHS" at 12634.96,1526.64 h60
  text "OTHER" at 13279.36,1526.64 h60
  text "PER ORDER" at 13676.42,1526.64 h60
  text "ADDITIONAL REQUIREMENTS:" at 11332.46,1385.64 h60
  text "MICROSECTION:" at 11407.23,1270.64 h60
  text "YES" at 12312.96,1270.64 h60
  text "REQUIRED" at 13174.46,1114.49 h60
  text "BARE BOARD ELEC. TEST:" at 11407.23,1111.64 h60
  text "NONE" at 12712.96,1111.64 h60
  text "X" at 13047.46,1111.64 h60
  text "PER ORDER" at 13766.46,1111.64 h60
  text "MANUFACTURER'S UL:" at 11407.23,954.64 h60
  text "RAIL" at 12572.96,950.35 h60
  text "METAL" at 13064.77,950.35 h60
  text "X" at 13440,950 h60
  text "SILK" at 13576.46,950.35 h60
  text ".Layer_Name" at 577,-858.49 h60
M11 Gerber Information:
  lines w10: -292,-930.17 6308,-930.17 ; -292,-726.83 6310,-726.83 ; -292,-523.5 -292,-1133.5 3713,-1133.5 6310,-1133.5 6310,-523.5 -291.5,-523.5 -291.5,-1133.5 1284,-1133.5 ; 2173,-1133.5 2173,-523.5 ; 3440,-726.83 3440,-523.5 ; 4280,-726.83 4280,-523.5 ; 4902,-1140 4902,-937.17
  text "ALL ARTWORK VIEWED FROM TOP SIDE" at -228.5,-655.67 h60
  text "BOARD #:" at 2248,-655.67 h60
  text ".PRJ_Number" at 2793.5,-655.67 h60
  text "REV:" at 3638,-655.67 h60
  text ".PCB_Rev" at 3929.5,-655.67 h60
  text "SVN REV:" at 4476,-655.67 h60
  text ".VersionControl_RevNumber" at 4982,-655.67 h60
  text "LAYER NAME =" at -228.5,-858.49 h60
  text "PLOT NAME =" at -228.5,-1064.34 h60
  text ".plot_File_Name" at 577,-1064.34 h60
  text "GENERATED    :" at 2250,-1064.34 h60
  text ".Print_Date" at 3119.5,-1064.34 h60
  text ".Print_Time" at 3848.5,-1064.34 h60
  text "TEXAS INSTRUMENTS" at 5113,-1064.34 h60
M12 Stackup:
  drawing of 295 lines, arcs and shapes, not listed
  text "Layer" at 9790.35,7845 h60
  text "Name" at 10200.26,7845 h60
  text "Material" at 11140,7845 h60
  text "Thickness" at 11999.77,7845 h60
  text "Constant" at 12649.6,7845 h60
  text "Board Layer Stack" at 13219.46,7845 h60
  text "1" at 9790.35,7725 h60
  text "Top Overlay" at 10200.26,7725 h60
  text "2" at 9790.35,7605 h60
  text "Top Solder" at 10200.26,7605 h60
  text "Solder Resist" at 11140,7605 h60
  text "0.40mil" at 11999.77,7605 h60
  text "3.5" at 12649.6,7605 h60
  text "3" at 9790.35,7485 h60
  text "Top Layer" at 10200.26,7485 h60
  text "Copper" at 11140,7485 h60
  text "1.40mil" at 11999.77,7485 h60
  text "4" at 9790.35,7365 h60
  text "Dielectric1" at 10200.26,7365 h60
  text "FR-4" at 11140,7365 h60
  text "59.20mil" at 11999.77,7365 h60
  text "4.8" at 12649.6,7365 h60
  text "5" at 9790.35,7245 h60
  text "Signal Layer 1" at 10200.26,7245 h60
  text "Copper" at 11140,7245 h60
  text "1.42mil" at 11999.77,7245 h60
  text "6" at 9790.35,7125 h60
  text "Dielectric 3" at 10200.26,7125 h60
  text "5.00mil" at 11999.77,7125 h60
  text "4.2" at 12649.6,7125 h60
  text "7" at 9790.35,7005 h60
  text "Signal Layer 2" at 10200.26,7005 h60
  text "Copper" at 11140,7005 h60
  text "1.42mil" at 11999.77,7005 h60
  text "8" at 9790.35,6885 h60
  text "Dielectric 2" at 10200.26,6885 h60
  text "10.00mil" at 11999.77,6885 h60
  text "4.2" at 12649.6,6885 h60
  text "9" at 9790.35,6765 h60
  text "Bottom Layer" at 10200.26,6765 h60
  text "Copper" at 11140,6765 h60
  text "1.40mil" at 11999.77,6765 h60
  text "10" at 9790.35,6645 h60
  text "Bottom Solder" at 10200.26,6645 h60
  text "Solder Resist" at 11140,6645 h60
  text "0.40mil" at 11999.77,6645 h60
  text "3.5" at 12649.6,6645 h60
  text "11" at 9790.35,6525 h60
  text "Bottom Overlay" at 10200.26,6525 h60
  text ".Layer_Name" at 577,-858.49 h60
M13 Component Bodies Top:
  text ".Layer_Name" at 577,-858.49 h60
M14 Component Bodies Bottom:
  text ".Layer_Name" at 577,-858.49 h60
M15 Courtyards Top:
  text ".Layer_Name" at 577,-858.49 h60
M16 Courtyards Bottom:
  text ".Layer_Name" at 577,-858.49 h60
Drill Drawing:
  circle w1: c34912.72,13581.04 r24.89
  lines w1: 34887.83,12822 34900.27,12822 34900.27,12809.56 34925.16,12809.56 34925.16,12822 34937.6,12822 34937.6,12846.89 34925.16,12846.89 34925.16,12859.33 34900.27,12859.33 34900.27,12846.89 34887.83,12846.89 34887.83,12822 ; 34887.83,13008.65 34937.6,13008.65 34912.72,12958.88 34887.83,13008.65 ; 34887.83,13120.64 34900.27,13120.64 34912.72,13108.2 34925.16,13120.64 34937.6,13120.64 34925.16,13133.08 34937.6,13145.53 34925.16,13145.53 34912.72,13157.97 34900.27,13145.53 34887.83,13145.53 34900.27,13133.08 34887.83,13120.64 ; 34887.83,13257.52 34912.72,13269.96 34937.6,13257.52 34925.16,13282.4 34937.6,13307.29 34912.72,13294.85 34887.83,13307.29 34900.27,13282.4 34887.83,13257.52 ; 34887.83,13431.72 34912.72,13406.84 34937.6,13431.72 34912.72,13456.61 34887.83,13431.72
  lines w12: 34820,12764.76 36938.02,12764.76 ; 34820,13660.68 36938.02,13660.68 ; 35190.36,12615.44 35190.36,13810 ; 35547.36,12615.44 35547.36,13810 ; 36208.93,12615.44 36208.93,13810 ; 36493.07,12615.44 36493.07,13810 ; 34820,12615.44 36938.02,12615.44 36938.02,13810 34820,13810 34820,12615.44
  text "Symbol" at 34909.59,13705.48 h72
  text "Quantity" at 35235.16,13705.48 h72
  text "Finished Hole Size" at 35592.16,13705.48 h72
  text "Plated" at 36253.72,13705.48 h72
  text "Hole Type" at 36537.86,13705.48 h72
  text "25" at 35235.16,13556.16 h60
  text "7.87mil (0.200mm)" at 35592.16,13556.16 h60
  text "PTH" at 36253.72,13556.16 h60
  text "Round" at 36537.86,13556.16 h60
  text "83" at 35235.16,13406.84 h60
  text "16.00mil (0.406mm)" at 35592.16,13406.84 h60
  text "PTH" at 36253.72,13406.84 h60
  text "Round" at 36537.86,13406.84 h60
  text "16" at 35235.16,13257.52 h60
  text "37.40mil (0.950mm)" at 35592.16,13257.52 h60
  text "PTH" at 36253.72,13257.52 h60
  text "Round" at 36537.86,13257.52 h60
  text "92" at 35235.16,13108.2 h60
  text "40.00mil (1.016mm)" at 35592.16,13108.2 h60
  text "PTH" at 36253.72,13108.2 h60
  text "Round" at 36537.86,13108.2 h60
  text "18" at 35235.16,12958.88 h60
  text "50.00mil (1.270mm)" at 35592.16,12958.88 h60
  text "PTH" at 36253.72,12958.88 h60
  text "Round" at 36537.86,12958.88 h60
  text "8" at 35235.16,12809.56 h60
  text "90.55mil (2.300mm)" at 35592.16,12809.56 h60
  text "PTH" at 36253.72,12809.56 h60
  text "Round" at 36537.86,12809.56 h60
  text "242 Total" at 35235.16,12660.24 h60
  text ".Layer_Name" at 577,-858.49 h60

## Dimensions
0,0 to 4320,0 on M2 Board Dimensions
0,0 to 0,3450 on M2 Board Dimensions
0,-400 to 1000,-400 on M2 Board Dimensions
